VERSION 5.8 ;
BUSBITCHARS "[]" ;
DIVIDERCHAR "/" ;

UNITS
  DATABASE MICRONS 2000 ;
END UNITS

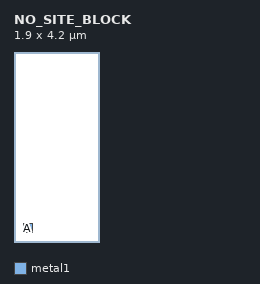
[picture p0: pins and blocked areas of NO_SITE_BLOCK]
MACRO NO_SITE_BLOCK
  CLASS BLOCK ;
  ORIGIN 0 0 ;
  SIZE 1.90 BY 4.20 ;
  SYMMETRY X Y ;
  PIN A
    DIRECTION INPUT ;
    PORT
      LAYER metal1 ;
        RECT 0.20 0.20 0.40 0.40 ;
    END
  END A
END NO_SITE_BLOCK

END LIBRARY
